# Generated by FakeRAM 2.0
VERSION 5.7 ;
BUSBITCHARS "[]" ;
PROPERTYDEFINITIONS
  MACRO width INTEGER ;
  MACRO depth INTEGER ;
  MACRO banks INTEGER ;
END PROPERTYDEFINITIONS
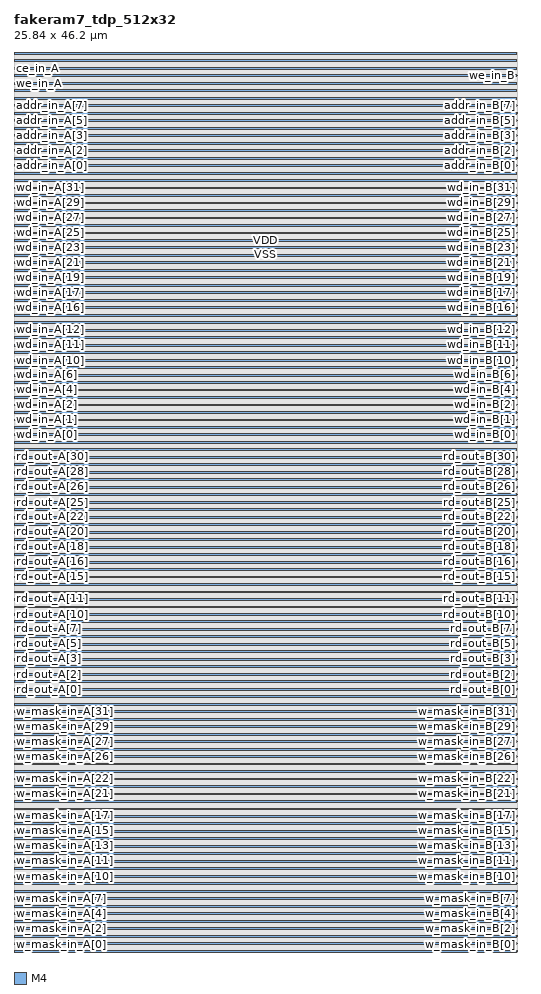
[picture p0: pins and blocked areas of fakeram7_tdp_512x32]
MACRO fakeram7_tdp_512x32
  PROPERTY width 32 ;
  PROPERTY depth 512 ;
  PROPERTY banks 4 ;
  FOREIGN fakeram7_tdp_512x32 0 0 ;
  SYMMETRY X Y ;
  SIZE 25.840 BY 46.200 ;
  CLASS BLOCK ;
  PIN w_mask_in_A[0]
    DIRECTION INPUT ;
    USE SIGNAL ;
    SHAPE ABUTMENT ;
    PORT
      LAYER M4 ;
      RECT 0.000 0.048 0.024 0.072 ;
    END
  END w_mask_in_A[0]
  PIN w_mask_in_B[0]
    DIRECTION INPUT ;
    USE SIGNAL ;
    SHAPE ABUTMENT ;
    PORT
      LAYER M4 ;
      RECT 25.816 0.048 25.840 0.072 ;
    END
  END w_mask_in_B[0]
  PIN w_mask_in_A[1]
    DIRECTION INPUT ;
    USE SIGNAL ;
    SHAPE ABUTMENT ;
    PORT
      LAYER M4 ;
      RECT 0.000 0.432 0.024 0.456 ;
    END
  END w_mask_in_A[1]
  PIN w_mask_in_B[1]
    DIRECTION INPUT ;
    USE SIGNAL ;
    SHAPE ABUTMENT ;
    PORT
      LAYER M4 ;
      RECT 25.816 0.432 25.840 0.456 ;
    END
  END w_mask_in_B[1]
  PIN w_mask_in_A[2]
    DIRECTION INPUT ;
    USE SIGNAL ;
    SHAPE ABUTMENT ;
    PORT
      LAYER M4 ;
      RECT 0.000 0.816 0.024 0.840 ;
    END
  END w_mask_in_A[2]
  PIN w_mask_in_B[2]
    DIRECTION INPUT ;
    USE SIGNAL ;
    SHAPE ABUTMENT ;
    PORT
      LAYER M4 ;
      RECT 25.816 0.816 25.840 0.840 ;
    END
  END w_mask_in_B[2]
  PIN w_mask_in_A[3]
    DIRECTION INPUT ;
    USE SIGNAL ;
    SHAPE ABUTMENT ;
    PORT
      LAYER M4 ;
      RECT 0.000 1.200 0.024 1.224 ;
    END
  END w_mask_in_A[3]
  PIN w_mask_in_B[3]
    DIRECTION INPUT ;
    USE SIGNAL ;
    SHAPE ABUTMENT ;
    PORT
      LAYER M4 ;
      RECT 25.816 1.200 25.840 1.224 ;
    END
  END w_mask_in_B[3]
  PIN w_mask_in_A[4]
    DIRECTION INPUT ;
    USE SIGNAL ;
    SHAPE ABUTMENT ;
    PORT
      LAYER M4 ;
      RECT 0.000 1.584 0.024 1.608 ;
    END
  END w_mask_in_A[4]
  PIN w_mask_in_B[4]
    DIRECTION INPUT ;
    USE SIGNAL ;
    SHAPE ABUTMENT ;
    PORT
      LAYER M4 ;
      RECT 25.816 1.584 25.840 1.608 ;
    END
  END w_mask_in_B[4]
  PIN w_mask_in_A[5]
    DIRECTION INPUT ;
    USE SIGNAL ;
    SHAPE ABUTMENT ;
    PORT
      LAYER M4 ;
      RECT 0.000 1.968 0.024 1.992 ;
    END
  END w_mask_in_A[5]
  PIN w_mask_in_B[5]
    DIRECTION INPUT ;
    USE SIGNAL ;
    SHAPE ABUTMENT ;
    PORT
      LAYER M4 ;
      RECT 25.816 1.968 25.840 1.992 ;
    END
  END w_mask_in_B[5]
  PIN w_mask_in_A[6]
    DIRECTION INPUT ;
    USE SIGNAL ;
    SHAPE ABUTMENT ;
    PORT
      LAYER M4 ;
      RECT 0.000 2.352 0.024 2.376 ;
    END
  END w_mask_in_A[6]
  PIN w_mask_in_B[6]
    DIRECTION INPUT ;
    USE SIGNAL ;
    SHAPE ABUTMENT ;
    PORT
      LAYER M4 ;
      RECT 25.816 2.352 25.840 2.376 ;
    END
  END w_mask_in_B[6]
  PIN w_mask_in_A[7]
    DIRECTION INPUT ;
    USE SIGNAL ;
    SHAPE ABUTMENT ;
    PORT
      LAYER M4 ;
      RECT 0.000 2.736 0.024 2.760 ;
    END
  END w_mask_in_A[7]
  PIN w_mask_in_B[7]
    DIRECTION INPUT ;
    USE SIGNAL ;
    SHAPE ABUTMENT ;
    PORT
      LAYER M4 ;
      RECT 25.816 2.736 25.840 2.760 ;
    END
  END w_mask_in_B[7]
  PIN w_mask_in_A[8]
    DIRECTION INPUT ;
    USE SIGNAL ;
    SHAPE ABUTMENT ;
    PORT
      LAYER M4 ;
      RECT 0.000 3.120 0.024 3.144 ;
    END
  END w_mask_in_A[8]
  PIN w_mask_in_B[8]
    DIRECTION INPUT ;
    USE SIGNAL ;
    SHAPE ABUTMENT ;
    PORT
      LAYER M4 ;
      RECT 25.816 3.120 25.840 3.144 ;
    END
  END w_mask_in_B[8]
  PIN w_mask_in_A[9]
    DIRECTION INPUT ;
    USE SIGNAL ;
    SHAPE ABUTMENT ;
    PORT
      LAYER M4 ;
      RECT 0.000 3.504 0.024 3.528 ;
    END
  END w_mask_in_A[9]
  PIN w_mask_in_B[9]
    DIRECTION INPUT ;
    USE SIGNAL ;
    SHAPE ABUTMENT ;
    PORT
      LAYER M4 ;
      RECT 25.816 3.504 25.840 3.528 ;
    END
  END w_mask_in_B[9]
  PIN w_mask_in_A[10]
    DIRECTION INPUT ;
    USE SIGNAL ;
    SHAPE ABUTMENT ;
    PORT
      LAYER M4 ;
      RECT 0.000 3.888 0.024 3.912 ;
    END
  END w_mask_in_A[10]
  PIN w_mask_in_B[10]
    DIRECTION INPUT ;
    USE SIGNAL ;
    SHAPE ABUTMENT ;
    PORT
      LAYER M4 ;
      RECT 25.816 3.888 25.840 3.912 ;
    END
  END w_mask_in_B[10]
  PIN w_mask_in_A[11]
    DIRECTION INPUT ;
    USE SIGNAL ;
    SHAPE ABUTMENT ;
    PORT
      LAYER M4 ;
      RECT 0.000 4.272 0.024 4.296 ;
    END
  END w_mask_in_A[11]
  PIN w_mask_in_B[11]
    DIRECTION INPUT ;
    USE SIGNAL ;
    SHAPE ABUTMENT ;
    PORT
      LAYER M4 ;
      RECT 25.816 4.272 25.840 4.296 ;
    END
  END w_mask_in_B[11]
  PIN w_mask_in_A[12]
    DIRECTION INPUT ;
    USE SIGNAL ;
    SHAPE ABUTMENT ;
    PORT
      LAYER M4 ;
      RECT 0.000 4.656 0.024 4.680 ;
    END
  END w_mask_in_A[12]
  PIN w_mask_in_B[12]
    DIRECTION INPUT ;
    USE SIGNAL ;
    SHAPE ABUTMENT ;
    PORT
      LAYER M4 ;
      RECT 25.816 4.656 25.840 4.680 ;
    END
  END w_mask_in_B[12]
  PIN w_mask_in_A[13]
    DIRECTION INPUT ;
    USE SIGNAL ;
    SHAPE ABUTMENT ;
    PORT
      LAYER M4 ;
      RECT 0.000 5.040 0.024 5.064 ;
    END
  END w_mask_in_A[13]
  PIN w_mask_in_B[13]
    DIRECTION INPUT ;
    USE SIGNAL ;
    SHAPE ABUTMENT ;
    PORT
      LAYER M4 ;
      RECT 25.816 5.040 25.840 5.064 ;
    END
  END w_mask_in_B[13]
  PIN w_mask_in_A[14]
    DIRECTION INPUT ;
    USE SIGNAL ;
    SHAPE ABUTMENT ;
    PORT
      LAYER M4 ;
      RECT 0.000 5.424 0.024 5.448 ;
    END
  END w_mask_in_A[14]
  PIN w_mask_in_B[14]
    DIRECTION INPUT ;
    USE SIGNAL ;
    SHAPE ABUTMENT ;
    PORT
      LAYER M4 ;
      RECT 25.816 5.424 25.840 5.448 ;
    END
  END w_mask_in_B[14]
  PIN w_mask_in_A[15]
    DIRECTION INPUT ;
    USE SIGNAL ;
    SHAPE ABUTMENT ;
    PORT
      LAYER M4 ;
      RECT 0.000 5.808 0.024 5.832 ;
    END
  END w_mask_in_A[15]
  PIN w_mask_in_B[15]
    DIRECTION INPUT ;
    USE SIGNAL ;
    SHAPE ABUTMENT ;
    PORT
      LAYER M4 ;
      RECT 25.816 5.808 25.840 5.832 ;
    END
  END w_mask_in_B[15]
  PIN w_mask_in_A[16]
    DIRECTION INPUT ;
    USE SIGNAL ;
    SHAPE ABUTMENT ;
    PORT
      LAYER M4 ;
      RECT 0.000 6.192 0.024 6.216 ;
    END
  END w_mask_in_A[16]
  PIN w_mask_in_B[16]
    DIRECTION INPUT ;
    USE SIGNAL ;
    SHAPE ABUTMENT ;
    PORT
      LAYER M4 ;
      RECT 25.816 6.192 25.840 6.216 ;
    END
  END w_mask_in_B[16]
  PIN w_mask_in_A[17]
    DIRECTION INPUT ;
    USE SIGNAL ;
    SHAPE ABUTMENT ;
    PORT
      LAYER M4 ;
      RECT 0.000 6.576 0.024 6.600 ;
    END
  END w_mask_in_A[17]
  PIN w_mask_in_B[17]
    DIRECTION INPUT ;
    USE SIGNAL ;
    SHAPE ABUTMENT ;
    PORT
      LAYER M4 ;
      RECT 25.816 6.576 25.840 6.600 ;
    END
  END w_mask_in_B[17]
  PIN w_mask_in_A[18]
    DIRECTION INPUT ;
    USE SIGNAL ;
    SHAPE ABUTMENT ;
    PORT
      LAYER M4 ;
      RECT 0.000 6.960 0.024 6.984 ;
    END
  END w_mask_in_A[18]
  PIN w_mask_in_B[18]
    DIRECTION INPUT ;
    USE SIGNAL ;
    SHAPE ABUTMENT ;
    PORT
      LAYER M4 ;
      RECT 25.816 6.960 25.840 6.984 ;
    END
  END w_mask_in_B[18]
  PIN w_mask_in_A[19]
    DIRECTION INPUT ;
    USE SIGNAL ;
    SHAPE ABUTMENT ;
    PORT
      LAYER M4 ;
      RECT 0.000 7.344 0.024 7.368 ;
    END
  END w_mask_in_A[19]
  PIN w_mask_in_B[19]
    DIRECTION INPUT ;
    USE SIGNAL ;
    SHAPE ABUTMENT ;
    PORT
      LAYER M4 ;
      RECT 25.816 7.344 25.840 7.368 ;
    END
  END w_mask_in_B[19]
  PIN w_mask_in_A[20]
    DIRECTION INPUT ;
    USE SIGNAL ;
    SHAPE ABUTMENT ;
    PORT
      LAYER M4 ;
      RECT 0.000 7.728 0.024 7.752 ;
    END
  END w_mask_in_A[20]
  PIN w_mask_in_B[20]
    DIRECTION INPUT ;
    USE SIGNAL ;
    SHAPE ABUTMENT ;
    PORT
      LAYER M4 ;
      RECT 25.816 7.728 25.840 7.752 ;
    END
  END w_mask_in_B[20]
  PIN w_mask_in_A[21]
    DIRECTION INPUT ;
    USE SIGNAL ;
    SHAPE ABUTMENT ;
    PORT
      LAYER M4 ;
      RECT 0.000 8.112 0.024 8.136 ;
    END
  END w_mask_in_A[21]
  PIN w_mask_in_B[21]
    DIRECTION INPUT ;
    USE SIGNAL ;
    SHAPE ABUTMENT ;
    PORT
      LAYER M4 ;
      RECT 25.816 8.112 25.840 8.136 ;
    END
  END w_mask_in_B[21]
  PIN w_mask_in_A[22]
    DIRECTION INPUT ;
    USE SIGNAL ;
    SHAPE ABUTMENT ;
    PORT
      LAYER M4 ;
      RECT 0.000 8.496 0.024 8.520 ;
    END
  END w_mask_in_A[22]
  PIN w_mask_in_B[22]
    DIRECTION INPUT ;
    USE SIGNAL ;
    SHAPE ABUTMENT ;
    PORT
      LAYER M4 ;
      RECT 25.816 8.496 25.840 8.520 ;
    END
  END w_mask_in_B[22]
  PIN w_mask_in_A[23]
    DIRECTION INPUT ;
    USE SIGNAL ;
    SHAPE ABUTMENT ;
    PORT
      LAYER M4 ;
      RECT 0.000 8.880 0.024 8.904 ;
    END
  END w_mask_in_A[23]
  PIN w_mask_in_B[23]
    DIRECTION INPUT ;
    USE SIGNAL ;
    SHAPE ABUTMENT ;
    PORT
      LAYER M4 ;
      RECT 25.816 8.880 25.840 8.904 ;
    END
  END w_mask_in_B[23]
  PIN w_mask_in_A[24]
    DIRECTION INPUT ;
    USE SIGNAL ;
    SHAPE ABUTMENT ;
    PORT
      LAYER M4 ;
      RECT 0.000 9.264 0.024 9.288 ;
    END
  END w_mask_in_A[24]
  PIN w_mask_in_B[24]
    DIRECTION INPUT ;
    USE SIGNAL ;
    SHAPE ABUTMENT ;
    PORT
      LAYER M4 ;
      RECT 25.816 9.264 25.840 9.288 ;
    END
  END w_mask_in_B[24]
  PIN w_mask_in_A[25]
    DIRECTION INPUT ;
    USE SIGNAL ;
    SHAPE ABUTMENT ;
    PORT
      LAYER M4 ;
      RECT 0.000 9.648 0.024 9.672 ;
    END
  END w_mask_in_A[25]
  PIN w_mask_in_B[25]
    DIRECTION INPUT ;
    USE SIGNAL ;
    SHAPE ABUTMENT ;
    PORT
      LAYER M4 ;
      RECT 25.816 9.648 25.840 9.672 ;
    END
  END w_mask_in_B[25]
  PIN w_mask_in_A[26]
    DIRECTION INPUT ;
    USE SIGNAL ;
    SHAPE ABUTMENT ;
    PORT
      LAYER M4 ;
      RECT 0.000 10.032 0.024 10.056 ;
    END
  END w_mask_in_A[26]
  PIN w_mask_in_B[26]
    DIRECTION INPUT ;
    USE SIGNAL ;
    SHAPE ABUTMENT ;
    PORT
      LAYER M4 ;
      RECT 25.816 10.032 25.840 10.056 ;
    END
  END w_mask_in_B[26]
  PIN w_mask_in_A[27]
    DIRECTION INPUT ;
    USE SIGNAL ;
    SHAPE ABUTMENT ;
    PORT
      LAYER M4 ;
      RECT 0.000 10.416 0.024 10.440 ;
    END
  END w_mask_in_A[27]
  PIN w_mask_in_B[27]
    DIRECTION INPUT ;
    USE SIGNAL ;
    SHAPE ABUTMENT ;
    PORT
      LAYER M4 ;
      RECT 25.816 10.416 25.840 10.440 ;
    END
  END w_mask_in_B[27]
  PIN w_mask_in_A[28]
    DIRECTION INPUT ;
    USE SIGNAL ;
    SHAPE ABUTMENT ;
    PORT
      LAYER M4 ;
      RECT 0.000 10.800 0.024 10.824 ;
    END
  END w_mask_in_A[28]
  PIN w_mask_in_B[28]
    DIRECTION INPUT ;
    USE SIGNAL ;
    SHAPE ABUTMENT ;
    PORT
      LAYER M4 ;
      RECT 25.816 10.800 25.840 10.824 ;
    END
  END w_mask_in_B[28]
  PIN w_mask_in_A[29]
    DIRECTION INPUT ;
    USE SIGNAL ;
    SHAPE ABUTMENT ;
    PORT
      LAYER M4 ;
      RECT 0.000 11.184 0.024 11.208 ;
    END
  END w_mask_in_A[29]
  PIN w_mask_in_B[29]
    DIRECTION INPUT ;
    USE SIGNAL ;
    SHAPE ABUTMENT ;
    PORT
      LAYER M4 ;
      RECT 25.816 11.184 25.840 11.208 ;
    END
  END w_mask_in_B[29]
  PIN w_mask_in_A[30]
    DIRECTION INPUT ;
    USE SIGNAL ;
    SHAPE ABUTMENT ;
    PORT
      LAYER M4 ;
      RECT 0.000 11.568 0.024 11.592 ;
    END
  END w_mask_in_A[30]
  PIN w_mask_in_B[30]
    DIRECTION INPUT ;
    USE SIGNAL ;
    SHAPE ABUTMENT ;
    PORT
      LAYER M4 ;
      RECT 25.816 11.568 25.840 11.592 ;
    END
  END w_mask_in_B[30]
  PIN w_mask_in_A[31]
    DIRECTION INPUT ;
    USE SIGNAL ;
    SHAPE ABUTMENT ;
    PORT
      LAYER M4 ;
      RECT 0.000 11.952 0.024 11.976 ;
    END
  END w_mask_in_A[31]
  PIN w_mask_in_B[31]
    DIRECTION INPUT ;
    USE SIGNAL ;
    SHAPE ABUTMENT ;
    PORT
      LAYER M4 ;
      RECT 25.816 11.952 25.840 11.976 ;
    END
  END w_mask_in_B[31]
  PIN rd_out_A[0]
    DIRECTION OUTPUT ;
    USE SIGNAL ;
    SHAPE ABUTMENT ;
    PORT
      LAYER M4 ;
      RECT 0.000 13.488 0.024 13.512 ;
    END
  END rd_out_A[0]
  PIN rd_out_B[0]
    DIRECTION OUTPUT ;
    USE SIGNAL ;
    SHAPE ABUTMENT ;
    PORT
      LAYER M4 ;
      RECT 25.816 13.488 25.840 13.512 ;
    END
  END rd_out_B[0]
  PIN rd_out_A[1]
    DIRECTION OUTPUT ;
    USE SIGNAL ;
    SHAPE ABUTMENT ;
    PORT
      LAYER M4 ;
      RECT 0.000 13.872 0.024 13.896 ;
    END
  END rd_out_A[1]
  PIN rd_out_B[1]
    DIRECTION OUTPUT ;
    USE SIGNAL ;
    SHAPE ABUTMENT ;
    PORT
      LAYER M4 ;
      RECT 25.816 13.872 25.840 13.896 ;
    END
  END rd_out_B[1]
  PIN rd_out_A[2]
    DIRECTION OUTPUT ;
    USE SIGNAL ;
    SHAPE ABUTMENT ;
    PORT
      LAYER M4 ;
      RECT 0.000 14.256 0.024 14.280 ;
    END
  END rd_out_A[2]
  PIN rd_out_B[2]
    DIRECTION OUTPUT ;
    USE SIGNAL ;
    SHAPE ABUTMENT ;
    PORT
      LAYER M4 ;
      RECT 25.816 14.256 25.840 14.280 ;
    END
  END rd_out_B[2]
  PIN rd_out_A[3]
    DIRECTION OUTPUT ;
    USE SIGNAL ;
    SHAPE ABUTMENT ;
    PORT
      LAYER M4 ;
      RECT 0.000 14.640 0.024 14.664 ;
    END
  END rd_out_A[3]
  PIN rd_out_B[3]
    DIRECTION OUTPUT ;
    USE SIGNAL ;
    SHAPE ABUTMENT ;
    PORT
      LAYER M4 ;
      RECT 25.816 14.640 25.840 14.664 ;
    END
  END rd_out_B[3]
  PIN rd_out_A[4]
    DIRECTION OUTPUT ;
    USE SIGNAL ;
    SHAPE ABUTMENT ;
    PORT
      LAYER M4 ;
      RECT 0.000 15.024 0.024 15.048 ;
    END
  END rd_out_A[4]
  PIN rd_out_B[4]
    DIRECTION OUTPUT ;
    USE SIGNAL ;
    SHAPE ABUTMENT ;
    PORT
      LAYER M4 ;
      RECT 25.816 15.024 25.840 15.048 ;
    END
  END rd_out_B[4]
  PIN rd_out_A[5]
    DIRECTION OUTPUT ;
    USE SIGNAL ;
    SHAPE ABUTMENT ;
    PORT
      LAYER M4 ;
      RECT 0.000 15.408 0.024 15.432 ;
    END
  END rd_out_A[5]
  PIN rd_out_B[5]
    DIRECTION OUTPUT ;
    USE SIGNAL ;
    SHAPE ABUTMENT ;
    PORT
      LAYER M4 ;
      RECT 25.816 15.408 25.840 15.432 ;
    END
  END rd_out_B[5]
  PIN rd_out_A[6]
    DIRECTION OUTPUT ;
    USE SIGNAL ;
    SHAPE ABUTMENT ;
    PORT
      LAYER M4 ;
      RECT 0.000 15.792 0.024 15.816 ;
    END
  END rd_out_A[6]
  PIN rd_out_B[6]
    DIRECTION OUTPUT ;
    USE SIGNAL ;
    SHAPE ABUTMENT ;
    PORT
      LAYER M4 ;
      RECT 25.816 15.792 25.840 15.816 ;
    END
  END rd_out_B[6]
  PIN rd_out_A[7]
    DIRECTION OUTPUT ;
    USE SIGNAL ;
    SHAPE ABUTMENT ;
    PORT
      LAYER M4 ;
      RECT 0.000 16.176 0.024 16.200 ;
    END
  END rd_out_A[7]
  PIN rd_out_B[7]
    DIRECTION OUTPUT ;
    USE SIGNAL ;
    SHAPE ABUTMENT ;
    PORT
      LAYER M4 ;
      RECT 25.816 16.176 25.840 16.200 ;
    END
  END rd_out_B[7]
  PIN rd_out_A[8]
    DIRECTION OUTPUT ;
    USE SIGNAL ;
    SHAPE ABUTMENT ;
    PORT
      LAYER M4 ;
      RECT 0.000 16.560 0.024 16.584 ;
    END
  END rd_out_A[8]
  PIN rd_out_B[8]
    DIRECTION OUTPUT ;
    USE SIGNAL ;
    SHAPE ABUTMENT ;
    PORT
      LAYER M4 ;
      RECT 25.816 16.560 25.840 16.584 ;
    END
  END rd_out_B[8]
  PIN rd_out_A[9]
    DIRECTION OUTPUT ;
    USE SIGNAL ;
    SHAPE ABUTMENT ;
    PORT
      LAYER M4 ;
      RECT 0.000 16.944 0.024 16.968 ;
    END
  END rd_out_A[9]
  PIN rd_out_B[9]
    DIRECTION OUTPUT ;
    USE SIGNAL ;
    SHAPE ABUTMENT ;
    PORT
      LAYER M4 ;
      RECT 25.816 16.944 25.840 16.968 ;
    END
  END rd_out_B[9]
  PIN rd_out_A[10]
    DIRECTION OUTPUT ;
    USE SIGNAL ;
    SHAPE ABUTMENT ;
    PORT
      LAYER M4 ;
      RECT 0.000 17.328 0.024 17.352 ;
    END
  END rd_out_A[10]
  PIN rd_out_B[10]
    DIRECTION OUTPUT ;
    USE SIGNAL ;
    SHAPE ABUTMENT ;
    PORT
      LAYER M4 ;
      RECT 25.816 17.328 25.840 17.352 ;
    END
  END rd_out_B[10]
  PIN rd_out_A[11]
    DIRECTION OUTPUT ;
    USE SIGNAL ;
    SHAPE ABUTMENT ;
    PORT
      LAYER M4 ;
      RECT 0.000 17.712 0.024 17.736 ;
    END
  END rd_out_A[11]
  PIN rd_out_B[11]
    DIRECTION OUTPUT ;
    USE SIGNAL ;
    SHAPE ABUTMENT ;
    PORT
      LAYER M4 ;
      RECT 25.816 17.712 25.840 17.736 ;
    END
  END rd_out_B[11]
  PIN rd_out_A[12]
    DIRECTION OUTPUT ;
    USE SIGNAL ;
    SHAPE ABUTMENT ;
    PORT
      LAYER M4 ;
      RECT 0.000 18.096 0.024 18.120 ;
    END
  END rd_out_A[12]
  PIN rd_out_B[12]
    DIRECTION OUTPUT ;
    USE SIGNAL ;
    SHAPE ABUTMENT ;
    PORT
      LAYER M4 ;
      RECT 25.816 18.096 25.840 18.120 ;
    END
  END rd_out_B[12]
  PIN rd_out_A[13]
    DIRECTION OUTPUT ;
    USE SIGNAL ;
    SHAPE ABUTMENT ;
    PORT
      LAYER M4 ;
      RECT 0.000 18.480 0.024 18.504 ;
    END
  END rd_out_A[13]
  PIN rd_out_B[13]
    DIRECTION OUTPUT ;
    USE SIGNAL ;
    SHAPE ABUTMENT ;
    PORT
      LAYER M4 ;
      RECT 25.816 18.480 25.840 18.504 ;
    END
  END rd_out_B[13]
  PIN rd_out_A[14]
    DIRECTION OUTPUT ;
    USE SIGNAL ;
    SHAPE ABUTMENT ;
    PORT
      LAYER M4 ;
      RECT 0.000 18.864 0.024 18.888 ;
    END
  END rd_out_A[14]
  PIN rd_out_B[14]
    DIRECTION OUTPUT ;
    USE SIGNAL ;
    SHAPE ABUTMENT ;
    PORT
      LAYER M4 ;
      RECT 25.816 18.864 25.840 18.888 ;
    END
  END rd_out_B[14]
  PIN rd_out_A[15]
    DIRECTION OUTPUT ;
    USE SIGNAL ;
    SHAPE ABUTMENT ;
    PORT
      LAYER M4 ;
      RECT 0.000 19.248 0.024 19.272 ;
    END
  END rd_out_A[15]
  PIN rd_out_B[15]
    DIRECTION OUTPUT ;
    USE SIGNAL ;
    SHAPE ABUTMENT ;
    PORT
      LAYER M4 ;
      RECT 25.816 19.248 25.840 19.272 ;
    END
  END rd_out_B[15]
  PIN rd_out_A[16]
    DIRECTION OUTPUT ;
    USE SIGNAL ;
    SHAPE ABUTMENT ;
    PORT
      LAYER M4 ;
      RECT 0.000 19.632 0.024 19.656 ;
    END
  END rd_out_A[16]
  PIN rd_out_B[16]
    DIRECTION OUTPUT ;
    USE SIGNAL ;
    SHAPE ABUTMENT ;
    PORT
      LAYER M4 ;
      RECT 25.816 19.632 25.840 19.656 ;
    END
  END rd_out_B[16]
  PIN rd_out_A[17]
    DIRECTION OUTPUT ;
    USE SIGNAL ;
    SHAPE ABUTMENT ;
    PORT
      LAYER M4 ;
      RECT 0.000 20.016 0.024 20.040 ;
    END
  END rd_out_A[17]
  PIN rd_out_B[17]
    DIRECTION OUTPUT ;
    USE SIGNAL ;
    SHAPE ABUTMENT ;
    PORT
      LAYER M4 ;
      RECT 25.816 20.016 25.840 20.040 ;
    END
  END rd_out_B[17]
  PIN rd_out_A[18]
    DIRECTION OUTPUT ;
    USE SIGNAL ;
    SHAPE ABUTMENT ;
    PORT
      LAYER M4 ;
      RECT 0.000 20.400 0.024 20.424 ;
    END
  END rd_out_A[18]
  PIN rd_out_B[18]
    DIRECTION OUTPUT ;
    USE SIGNAL ;
    SHAPE ABUTMENT ;
    PORT
      LAYER M4 ;
      RECT 25.816 20.400 25.840 20.424 ;
    END
  END rd_out_B[18]
  PIN rd_out_A[19]
    DIRECTION OUTPUT ;
    USE SIGNAL ;
    SHAPE ABUTMENT ;
    PORT
      LAYER M4 ;
      RECT 0.000 20.784 0.024 20.808 ;
    END
  END rd_out_A[19]
  PIN rd_out_B[19]
    DIRECTION OUTPUT ;
    USE SIGNAL ;
    SHAPE ABUTMENT ;
    PORT
      LAYER M4 ;
      RECT 25.816 20.784 25.840 20.808 ;
    END
  END rd_out_B[19]
  PIN rd_out_A[20]
    DIRECTION OUTPUT ;
    USE SIGNAL ;
    SHAPE ABUTMENT ;
    PORT
      LAYER M4 ;
      RECT 0.000 21.168 0.024 21.192 ;
    END
  END rd_out_A[20]
  PIN rd_out_B[20]
    DIRECTION OUTPUT ;
    USE SIGNAL ;
    SHAPE ABUTMENT ;
    PORT
      LAYER M4 ;
      RECT 25.816 21.168 25.840 21.192 ;
    END
  END rd_out_B[20]
  PIN rd_out_A[21]
    DIRECTION OUTPUT ;
    USE SIGNAL ;
    SHAPE ABUTMENT ;
    PORT
      LAYER M4 ;
      RECT 0.000 21.552 0.024 21.576 ;
    END
  END rd_out_A[21]
  PIN rd_out_B[21]
    DIRECTION OUTPUT ;
    USE SIGNAL ;
    SHAPE ABUTMENT ;
    PORT
      LAYER M4 ;
      RECT 25.816 21.552 25.840 21.576 ;
    END
  END rd_out_B[21]
  PIN rd_out_A[22]
    DIRECTION OUTPUT ;
    USE SIGNAL ;
    SHAPE ABUTMENT ;
    PORT
      LAYER M4 ;
      RECT 0.000 21.936 0.024 21.960 ;
    END
  END rd_out_A[22]
  PIN rd_out_B[22]
    DIRECTION OUTPUT ;
    USE SIGNAL ;
    SHAPE ABUTMENT ;
    PORT
      LAYER M4 ;
      RECT 25.816 21.936 25.840 21.960 ;
    END
  END rd_out_B[22]
  PIN rd_out_A[23]
    DIRECTION OUTPUT ;
    USE SIGNAL ;
    SHAPE ABUTMENT ;
    PORT
      LAYER M4 ;
      RECT 0.000 22.320 0.024 22.344 ;
    END
  END rd_out_A[23]
  PIN rd_out_B[23]
    DIRECTION OUTPUT ;
    USE SIGNAL ;
    SHAPE ABUTMENT ;
    PORT
      LAYER M4 ;
      RECT 25.816 22.320 25.840 22.344 ;
    END
  END rd_out_B[23]
  PIN rd_out_A[24]
    DIRECTION OUTPUT ;
    USE SIGNAL ;
    SHAPE ABUTMENT ;
    PORT
      LAYER M4 ;
      RECT 0.000 22.704 0.024 22.728 ;
    END
  END rd_out_A[24]
  PIN rd_out_B[24]
    DIRECTION OUTPUT ;
    USE SIGNAL ;
    SHAPE ABUTMENT ;
    PORT
      LAYER M4 ;
      RECT 25.816 22.704 25.840 22.728 ;
    END
  END rd_out_B[24]
  PIN rd_out_A[25]
    DIRECTION OUTPUT ;
    USE SIGNAL ;
    SHAPE ABUTMENT ;
    PORT
      LAYER M4 ;
      RECT 0.000 23.088 0.024 23.112 ;
    END
  END rd_out_A[25]
  PIN rd_out_B[25]
    DIRECTION OUTPUT ;
    USE SIGNAL ;
    SHAPE ABUTMENT ;
    PORT
      LAYER M4 ;
      RECT 25.816 23.088 25.840 23.112 ;
    END
  END rd_out_B[25]
  PIN rd_out_A[26]
    DIRECTION OUTPUT ;
    USE SIGNAL ;
    SHAPE ABUTMENT ;
    PORT
      LAYER M4 ;
      RECT 0.000 23.472 0.024 23.496 ;
    END
  END rd_out_A[26]
  PIN rd_out_B[26]
    DIRECTION OUTPUT ;
    USE SIGNAL ;
    SHAPE ABUTMENT ;
    PORT
      LAYER M4 ;
      RECT 25.816 23.472 25.840 23.496 ;
    END
  END rd_out_B[26]
  PIN rd_out_A[27]
    DIRECTION OUTPUT ;
    USE SIGNAL ;
    SHAPE ABUTMENT ;
    PORT
      LAYER M4 ;
      RECT 0.000 23.856 0.024 23.880 ;
    END
  END rd_out_A[27]
  PIN rd_out_B[27]
    DIRECTION OUTPUT ;
    USE SIGNAL ;
    SHAPE ABUTMENT ;
    PORT
      LAYER M4 ;
      RECT 25.816 23.856 25.840 23.880 ;
    END
  END rd_out_B[27]
  PIN rd_out_A[28]
    DIRECTION OUTPUT ;
    USE SIGNAL ;
    SHAPE ABUTMENT ;
    PORT
      LAYER M4 ;
      RECT 0.000 24.240 0.024 24.264 ;
    END
  END rd_out_A[28]
  PIN rd_out_B[28]
    DIRECTION OUTPUT ;
    USE SIGNAL ;
    SHAPE ABUTMENT ;
    PORT
      LAYER M4 ;
      RECT 25.816 24.240 25.840 24.264 ;
    END
  END rd_out_B[28]
  PIN rd_out_A[29]
    DIRECTION OUTPUT ;
    USE SIGNAL ;
    SHAPE ABUTMENT ;
    PORT
      LAYER M4 ;
      RECT 0.000 24.624 0.024 24.648 ;
    END
  END rd_out_A[29]
  PIN rd_out_B[29]
    DIRECTION OUTPUT ;
    USE SIGNAL ;
    SHAPE ABUTMENT ;
    PORT
      LAYER M4 ;
      RECT 25.816 24.624 25.840 24.648 ;
    END
  END rd_out_B[29]
  PIN rd_out_A[30]
    DIRECTION OUTPUT ;
    USE SIGNAL ;
    SHAPE ABUTMENT ;
    PORT
      LAYER M4 ;
      RECT 0.000 25.008 0.024 25.032 ;
    END
  END rd_out_A[30]
  PIN rd_out_B[30]
    DIRECTION OUTPUT ;
    USE SIGNAL ;
    SHAPE ABUTMENT ;
    PORT
      LAYER M4 ;
      RECT 25.816 25.008 25.840 25.032 ;
    END
  END rd_out_B[30]
  PIN rd_out_A[31]
    DIRECTION OUTPUT ;
    USE SIGNAL ;
    SHAPE ABUTMENT ;
    PORT
      LAYER M4 ;
      RECT 0.000 25.392 0.024 25.416 ;
    END
  END rd_out_A[31]
  PIN rd_out_B[31]
    DIRECTION OUTPUT ;
    USE SIGNAL ;
    SHAPE ABUTMENT ;
    PORT
      LAYER M4 ;
      RECT 25.816 25.392 25.840 25.416 ;
    END
  END rd_out_B[31]
  PIN wd_in_A[0]
    DIRECTION INPUT ;
    USE SIGNAL ;
    SHAPE ABUTMENT ;
    PORT
      LAYER M4 ;
      RECT 0.000 26.928 0.024 26.952 ;
    END
  END wd_in_A[0]
  PIN wd_in_B[0]
    DIRECTION INPUT ;
    USE SIGNAL ;
    SHAPE ABUTMENT ;
    PORT
      LAYER M4 ;
      RECT 25.816 26.928 25.840 26.952 ;
    END
  END wd_in_B[0]
  PIN wd_in_A[1]
    DIRECTION INPUT ;
    USE SIGNAL ;
    SHAPE ABUTMENT ;
    PORT
      LAYER M4 ;
      RECT 0.000 27.312 0.024 27.336 ;
    END
  END wd_in_A[1]
  PIN wd_in_B[1]
    DIRECTION INPUT ;
    USE SIGNAL ;
    SHAPE ABUTMENT ;
    PORT
      LAYER M4 ;
      RECT 25.816 27.312 25.840 27.336 ;
    END
  END wd_in_B[1]
  PIN wd_in_A[2]
    DIRECTION INPUT ;
    USE SIGNAL ;
    SHAPE ABUTMENT ;
    PORT
      LAYER M4 ;
      RECT 0.000 27.696 0.024 27.720 ;
    END
  END wd_in_A[2]
  PIN wd_in_B[2]
    DIRECTION INPUT ;
    USE SIGNAL ;
    SHAPE ABUTMENT ;
    PORT
      LAYER M4 ;
      RECT 25.816 27.696 25.840 27.720 ;
    END
  END wd_in_B[2]
  PIN wd_in_A[3]
    DIRECTION INPUT ;
    USE SIGNAL ;
    SHAPE ABUTMENT ;
    PORT
      LAYER M4 ;
      RECT 0.000 28.080 0.024 28.104 ;
    END
  END wd_in_A[3]
  PIN wd_in_B[3]
    DIRECTION INPUT ;
    USE SIGNAL ;
    SHAPE ABUTMENT ;
    PORT
      LAYER M4 ;
      RECT 25.816 28.080 25.840 28.104 ;
    END
  END wd_in_B[3]
  PIN wd_in_A[4]
    DIRECTION INPUT ;
    USE SIGNAL ;
    SHAPE ABUTMENT ;
    PORT
      LAYER M4 ;
      RECT 0.000 28.464 0.024 28.488 ;
    END
  END wd_in_A[4]
  PIN wd_in_B[4]
    DIRECTION INPUT ;
    USE SIGNAL ;
    SHAPE ABUTMENT ;
    PORT
      LAYER M4 ;
      RECT 25.816 28.464 25.840 28.488 ;
    END
  END wd_in_B[4]
  PIN wd_in_A[5]
    DIRECTION INPUT ;
    USE SIGNAL ;
    SHAPE ABUTMENT ;
    PORT
      LAYER M4 ;
      RECT 0.000 28.848 0.024 28.872 ;
    END
  END wd_in_A[5]
  PIN wd_in_B[5]
    DIRECTION INPUT ;
    USE SIGNAL ;
    SHAPE ABUTMENT ;
    PORT
      LAYER M4 ;
      RECT 25.816 28.848 25.840 28.872 ;
    END
  END wd_in_B[5]
  PIN wd_in_A[6]
    DIRECTION INPUT ;
    USE SIGNAL ;
    SHAPE ABUTMENT ;
    PORT
      LAYER M4 ;
      RECT 0.000 29.232 0.024 29.256 ;
    END
  END wd_in_A[6]
  PIN wd_in_B[6]
    DIRECTION INPUT ;
    USE SIGNAL ;
    SHAPE ABUTMENT ;
    PORT
      LAYER M4 ;
      RECT 25.816 29.232 25.840 29.256 ;
    END
  END wd_in_B[6]
  PIN wd_in_A[7]
    DIRECTION INPUT ;
    USE SIGNAL ;
    SHAPE ABUTMENT ;
    PORT
      LAYER M4 ;
      RECT 0.000 29.616 0.024 29.640 ;
    END
  END wd_in_A[7]
  PIN wd_in_B[7]
    DIRECTION INPUT ;
    USE SIGNAL ;
    SHAPE ABUTMENT ;
    PORT
      LAYER M4 ;
      RECT 25.816 29.616 25.840 29.640 ;
    END
  END wd_in_B[7]
  PIN wd_in_A[8]
    DIRECTION INPUT ;
    USE SIGNAL ;
    SHAPE ABUTMENT ;
    PORT
      LAYER M4 ;
      RECT 0.000 30.000 0.024 30.024 ;
    END
  END wd_in_A[8]
  PIN wd_in_B[8]
    DIRECTION INPUT ;
    USE SIGNAL ;
    SHAPE ABUTMENT ;
    PORT
      LAYER M4 ;
      RECT 25.816 30.000 25.840 30.024 ;
    END
  END wd_in_B[8]
  PIN wd_in_A[9]
    DIRECTION INPUT ;
    USE SIGNAL ;
    SHAPE ABUTMENT ;
    PORT
      LAYER M4 ;
      RECT 0.000 30.384 0.024 30.408 ;
    END
  END wd_in_A[9]
  PIN wd_in_B[9]
    DIRECTION INPUT ;
    USE SIGNAL ;
    SHAPE ABUTMENT ;
    PORT
      LAYER M4 ;
      RECT 25.816 30.384 25.840 30.408 ;
    END
  END wd_in_B[9]
  PIN wd_in_A[10]
    DIRECTION INPUT ;
    USE SIGNAL ;
    SHAPE ABUTMENT ;
    PORT
      LAYER M4 ;
      RECT 0.000 30.768 0.024 30.792 ;
    END
  END wd_in_A[10]
  PIN wd_in_B[10]
    DIRECTION INPUT ;
    USE SIGNAL ;
    SHAPE ABUTMENT ;
    PORT
      LAYER M4 ;
      RECT 25.816 30.768 25.840 30.792 ;
    END
  END wd_in_B[10]
  PIN wd_in_A[11]
    DIRECTION INPUT ;
    USE SIGNAL ;
    SHAPE ABUTMENT ;
    PORT
      LAYER M4 ;
      RECT 0.000 31.152 0.024 31.176 ;
    END
  END wd_in_A[11]
  PIN wd_in_B[11]
    DIRECTION INPUT ;
    USE SIGNAL ;
    SHAPE ABUTMENT ;
    PORT
      LAYER M4 ;
      RECT 25.816 31.152 25.840 31.176 ;
    END
  END wd_in_B[11]
  PIN wd_in_A[12]
    DIRECTION INPUT ;
    USE SIGNAL ;
    SHAPE ABUTMENT ;
    PORT
      LAYER M4 ;
      RECT 0.000 31.536 0.024 31.560 ;
    END
  END wd_in_A[12]
  PIN wd_in_B[12]
    DIRECTION INPUT ;
    USE SIGNAL ;
    SHAPE ABUTMENT ;
    PORT
      LAYER M4 ;
      RECT 25.816 31.536 25.840 31.560 ;
    END
  END wd_in_B[12]
  PIN wd_in_A[13]
    DIRECTION INPUT ;
    USE SIGNAL ;
    SHAPE ABUTMENT ;
    PORT
      LAYER M4 ;
      RECT 0.000 31.920 0.024 31.944 ;
    END
  END wd_in_A[13]
  PIN wd_in_B[13]
    DIRECTION INPUT ;
    USE SIGNAL ;
    SHAPE ABUTMENT ;
    PORT
      LAYER M4 ;
      RECT 25.816 31.920 25.840 31.944 ;
    END
  END wd_in_B[13]
  PIN wd_in_A[14]
    DIRECTION INPUT ;
    USE SIGNAL ;
    SHAPE ABUTMENT ;
    PORT
      LAYER M4 ;
      RECT 0.000 32.304 0.024 32.328 ;
    END
  END wd_in_A[14]
  PIN wd_in_B[14]
    DIRECTION INPUT ;
    USE SIGNAL ;
    SHAPE ABUTMENT ;
    PORT
      LAYER M4 ;
      RECT 25.816 32.304 25.840 32.328 ;
    END
  END wd_in_B[14]
  PIN wd_in_A[15]
    DIRECTION INPUT ;
    USE SIGNAL ;
    SHAPE ABUTMENT ;
    PORT
      LAYER M4 ;
      RECT 0.000 32.688 0.024 32.712 ;
    END
  END wd_in_A[15]
  PIN wd_in_B[15]
    DIRECTION INPUT ;
    USE SIGNAL ;
    SHAPE ABUTMENT ;
    PORT
      LAYER M4 ;
      RECT 25.816 32.688 25.840 32.712 ;
    END
  END wd_in_B[15]
  PIN wd_in_A[16]
    DIRECTION INPUT ;
    USE SIGNAL ;
    SHAPE ABUTMENT ;
    PORT
      LAYER M4 ;
      RECT 0.000 33.072 0.024 33.096 ;
    END
  END wd_in_A[16]
  PIN wd_in_B[16]
    DIRECTION INPUT ;
    USE SIGNAL ;
    SHAPE ABUTMENT ;
    PORT
      LAYER M4 ;
      RECT 25.816 33.072 25.840 33.096 ;
    END
  END wd_in_B[16]
  PIN wd_in_A[17]
    DIRECTION INPUT ;
    USE SIGNAL ;
    SHAPE ABUTMENT ;
    PORT
      LAYER M4 ;
      RECT 0.000 33.456 0.024 33.480 ;
    END
  END wd_in_A[17]
  PIN wd_in_B[17]
    DIRECTION INPUT ;
    USE SIGNAL ;
    SHAPE ABUTMENT ;
    PORT
      LAYER M4 ;
      RECT 25.816 33.456 25.840 33.480 ;
    END
  END wd_in_B[17]
  PIN wd_in_A[18]
    DIRECTION INPUT ;
    USE SIGNAL ;
    SHAPE ABUTMENT ;
    PORT
      LAYER M4 ;
      RECT 0.000 33.840 0.024 33.864 ;
    END
  END wd_in_A[18]
  PIN wd_in_B[18]
    DIRECTION INPUT ;
    USE SIGNAL ;
    SHAPE ABUTMENT ;
    PORT
      LAYER M4 ;
      RECT 25.816 33.840 25.840 33.864 ;
    END
  END wd_in_B[18]
  PIN wd_in_A[19]
    DIRECTION INPUT ;
    USE SIGNAL ;
    SHAPE ABUTMENT ;
    PORT
      LAYER M4 ;
      RECT 0.000 34.224 0.024 34.248 ;
    END
  END wd_in_A[19]
  PIN wd_in_B[19]
    DIRECTION INPUT ;
    USE SIGNAL ;
    SHAPE ABUTMENT ;
    PORT
      LAYER M4 ;
      RECT 25.816 34.224 25.840 34.248 ;
    END
  END wd_in_B[19]
  PIN wd_in_A[20]
    DIRECTION INPUT ;
    USE SIGNAL ;
    SHAPE ABUTMENT ;
    PORT
      LAYER M4 ;
      RECT 0.000 34.608 0.024 34.632 ;
    END
  END wd_in_A[20]
  PIN wd_in_B[20]
    DIRECTION INPUT ;
    USE SIGNAL ;
    SHAPE ABUTMENT ;
    PORT
      LAYER M4 ;
      RECT 25.816 34.608 25.840 34.632 ;
    END
  END wd_in_B[20]
  PIN wd_in_A[21]
    DIRECTION INPUT ;
    USE SIGNAL ;
    SHAPE ABUTMENT ;
    PORT
      LAYER M4 ;
      RECT 0.000 34.992 0.024 35.016 ;
    END
  END wd_in_A[21]
  PIN wd_in_B[21]
    DIRECTION INPUT ;
    USE SIGNAL ;
    SHAPE ABUTMENT ;
    PORT
      LAYER M4 ;
      RECT 25.816 34.992 25.840 35.016 ;
    END
  END wd_in_B[21]
  PIN wd_in_A[22]
    DIRECTION INPUT ;
    USE SIGNAL ;
    SHAPE ABUTMENT ;
    PORT
      LAYER M4 ;
      RECT 0.000 35.376 0.024 35.400 ;
    END
  END wd_in_A[22]
  PIN wd_in_B[22]
    DIRECTION INPUT ;
    USE SIGNAL ;
    SHAPE ABUTMENT ;
    PORT
      LAYER M4 ;
      RECT 25.816 35.376 25.840 35.400 ;
    END
  END wd_in_B[22]
  PIN wd_in_A[23]
    DIRECTION INPUT ;
    USE SIGNAL ;
    SHAPE ABUTMENT ;
    PORT
      LAYER M4 ;
      RECT 0.000 35.760 0.024 35.784 ;
    END
  END wd_in_A[23]
  PIN wd_in_B[23]
    DIRECTION INPUT ;
    USE SIGNAL ;
    SHAPE ABUTMENT ;
    PORT
      LAYER M4 ;
      RECT 25.816 35.760 25.840 35.784 ;
    END
  END wd_in_B[23]
  PIN wd_in_A[24]
    DIRECTION INPUT ;
    USE SIGNAL ;
    SHAPE ABUTMENT ;
    PORT
      LAYER M4 ;
      RECT 0.000 36.144 0.024 36.168 ;
    END
  END wd_in_A[24]
  PIN wd_in_B[24]
    DIRECTION INPUT ;
    USE SIGNAL ;
    SHAPE ABUTMENT ;
    PORT
      LAYER M4 ;
      RECT 25.816 36.144 25.840 36.168 ;
    END
  END wd_in_B[24]
  PIN wd_in_A[25]
    DIRECTION INPUT ;
    USE SIGNAL ;
    SHAPE ABUTMENT ;
    PORT
      LAYER M4 ;
      RECT 0.000 36.528 0.024 36.552 ;
    END
  END wd_in_A[25]
  PIN wd_in_B[25]
    DIRECTION INPUT ;
    USE SIGNAL ;
    SHAPE ABUTMENT ;
    PORT
      LAYER M4 ;
      RECT 25.816 36.528 25.840 36.552 ;
    END
  END wd_in_B[25]
  PIN wd_in_A[26]
    DIRECTION INPUT ;
    USE SIGNAL ;
    SHAPE ABUTMENT ;
    PORT
      LAYER M4 ;
      RECT 0.000 36.912 0.024 36.936 ;
    END
  END wd_in_A[26]
  PIN wd_in_B[26]
    DIRECTION INPUT ;
    USE SIGNAL ;
    SHAPE ABUTMENT ;
    PORT
      LAYER M4 ;
      RECT 25.816 36.912 25.840 36.936 ;
    END
  END wd_in_B[26]
  PIN wd_in_A[27]
    DIRECTION INPUT ;
    USE SIGNAL ;
    SHAPE ABUTMENT ;
    PORT
      LAYER M4 ;
      RECT 0.000 37.296 0.024 37.320 ;
    END
  END wd_in_A[27]
  PIN wd_in_B[27]
    DIRECTION INPUT ;
    USE SIGNAL ;
    SHAPE ABUTMENT ;
    PORT
      LAYER M4 ;
      RECT 25.816 37.296 25.840 37.320 ;
    END
  END wd_in_B[27]
  PIN wd_in_A[28]
    DIRECTION INPUT ;
    USE SIGNAL ;
    SHAPE ABUTMENT ;
    PORT
      LAYER M4 ;
      RECT 0.000 37.680 0.024 37.704 ;
    END
  END wd_in_A[28]
  PIN wd_in_B[28]
    DIRECTION INPUT ;
    USE SIGNAL ;
    SHAPE ABUTMENT ;
    PORT
      LAYER M4 ;
      RECT 25.816 37.680 25.840 37.704 ;
    END
  END wd_in_B[28]
  PIN wd_in_A[29]
    DIRECTION INPUT ;
    USE SIGNAL ;
    SHAPE ABUTMENT ;
    PORT
      LAYER M4 ;
      RECT 0.000 38.064 0.024 38.088 ;
    END
  END wd_in_A[29]
  PIN wd_in_B[29]
    DIRECTION INPUT ;
    USE SIGNAL ;
    SHAPE ABUTMENT ;
    PORT
      LAYER M4 ;
      RECT 25.816 38.064 25.840 38.088 ;
    END
  END wd_in_B[29]
  PIN wd_in_A[30]
    DIRECTION INPUT ;
    USE SIGNAL ;
    SHAPE ABUTMENT ;
    PORT
      LAYER M4 ;
      RECT 0.000 38.448 0.024 38.472 ;
    END
  END wd_in_A[30]
  PIN wd_in_B[30]
    DIRECTION INPUT ;
    USE SIGNAL ;
    SHAPE ABUTMENT ;
    PORT
      LAYER M4 ;
      RECT 25.816 38.448 25.840 38.472 ;
    END
  END wd_in_B[30]
  PIN wd_in_A[31]
    DIRECTION INPUT ;
    USE SIGNAL ;
    SHAPE ABUTMENT ;
    PORT
      LAYER M4 ;
      RECT 0.000 38.832 0.024 38.856 ;
    END
  END wd_in_A[31]
  PIN wd_in_B[31]
    DIRECTION INPUT ;
    USE SIGNAL ;
    SHAPE ABUTMENT ;
    PORT
      LAYER M4 ;
      RECT 25.816 38.832 25.840 38.856 ;
    END
  END wd_in_B[31]
  PIN addr_in_A[0]
    DIRECTION INPUT ;
    USE SIGNAL ;
    SHAPE ABUTMENT ;
    PORT
      LAYER M4 ;
      RECT 0.000 40.368 0.024 40.392 ;
    END
  END addr_in_A[0]
  PIN addr_in_B[0]
    DIRECTION INPUT ;
    USE SIGNAL ;
    SHAPE ABUTMENT ;
    PORT
      LAYER M4 ;
      RECT 25.816 40.368 25.840 40.392 ;
    END
  END addr_in_B[0]
  PIN addr_in_A[1]
    DIRECTION INPUT ;
    USE SIGNAL ;
    SHAPE ABUTMENT ;
    PORT
      LAYER M4 ;
      RECT 0.000 40.752 0.024 40.776 ;
    END
  END addr_in_A[1]
  PIN addr_in_B[1]
    DIRECTION INPUT ;
    USE SIGNAL ;
    SHAPE ABUTMENT ;
    PORT
      LAYER M4 ;
      RECT 25.816 40.752 25.840 40.776 ;
    END
  END addr_in_B[1]
  PIN addr_in_A[2]
    DIRECTION INPUT ;
    USE SIGNAL ;
    SHAPE ABUTMENT ;
    PORT
      LAYER M4 ;
      RECT 0.000 41.136 0.024 41.160 ;
    END
  END addr_in_A[2]
  PIN addr_in_B[2]
    DIRECTION INPUT ;
    USE SIGNAL ;
    SHAPE ABUTMENT ;
    PORT
      LAYER M4 ;
      RECT 25.816 41.136 25.840 41.160 ;
    END
  END addr_in_B[2]
  PIN addr_in_A[3]
    DIRECTION INPUT ;
    USE SIGNAL ;
    SHAPE ABUTMENT ;
    PORT
      LAYER M4 ;
      RECT 0.000 41.520 0.024 41.544 ;
    END
  END addr_in_A[3]
  PIN addr_in_B[3]
    DIRECTION INPUT ;
    USE SIGNAL ;
    SHAPE ABUTMENT ;
    PORT
      LAYER M4 ;
      RECT 25.816 41.520 25.840 41.544 ;
    END
  END addr_in_B[3]
  PIN addr_in_A[4]
    DIRECTION INPUT ;
    USE SIGNAL ;
    SHAPE ABUTMENT ;
    PORT
      LAYER M4 ;
      RECT 0.000 41.904 0.024 41.928 ;
    END
  END addr_in_A[4]
  PIN addr_in_B[4]
    DIRECTION INPUT ;
    USE SIGNAL ;
    SHAPE ABUTMENT ;
    PORT
      LAYER M4 ;
      RECT 25.816 41.904 25.840 41.928 ;
    END
  END addr_in_B[4]
  PIN addr_in_A[5]
    DIRECTION INPUT ;
    USE SIGNAL ;
    SHAPE ABUTMENT ;
    PORT
      LAYER M4 ;
      RECT 0.000 42.288 0.024 42.312 ;
    END
  END addr_in_A[5]
  PIN addr_in_B[5]
    DIRECTION INPUT ;
    USE SIGNAL ;
    SHAPE ABUTMENT ;
    PORT
      LAYER M4 ;
      RECT 25.816 42.288 25.840 42.312 ;
    END
  END addr_in_B[5]
  PIN addr_in_A[6]
    DIRECTION INPUT ;
    USE SIGNAL ;
    SHAPE ABUTMENT ;
    PORT
      LAYER M4 ;
      RECT 0.000 42.672 0.024 42.696 ;
    END
  END addr_in_A[6]
  PIN addr_in_B[6]
    DIRECTION INPUT ;
    USE SIGNAL ;
    SHAPE ABUTMENT ;
    PORT
      LAYER M4 ;
      RECT 25.816 42.672 25.840 42.696 ;
    END
  END addr_in_B[6]
  PIN addr_in_A[7]
    DIRECTION INPUT ;
    USE SIGNAL ;
    SHAPE ABUTMENT ;
    PORT
      LAYER M4 ;
      RECT 0.000 43.056 0.024 43.080 ;
    END
  END addr_in_A[7]
  PIN addr_in_B[7]
    DIRECTION INPUT ;
    USE SIGNAL ;
    SHAPE ABUTMENT ;
    PORT
      LAYER M4 ;
      RECT 25.816 43.056 25.840 43.080 ;
    END
  END addr_in_B[7]
  PIN addr_in_A[8]
    DIRECTION INPUT ;
    USE SIGNAL ;
    SHAPE ABUTMENT ;
    PORT
      LAYER M4 ;
      RECT 0.000 43.440 0.024 43.464 ;
    END
  END addr_in_A[8]
  PIN addr_in_B[8]
    DIRECTION INPUT ;
    USE SIGNAL ;
    SHAPE ABUTMENT ;
    PORT
      LAYER M4 ;
      RECT 25.816 43.440 25.840 43.464 ;
    END
  END addr_in_B[8]
  PIN we_in_A
    DIRECTION INPUT ;
    USE SIGNAL ;
    SHAPE ABUTMENT ;
    PORT
      LAYER M4 ;
      RECT 0.000 44.976 0.024 45.000 ;
    END
  END we_in_A
  PIN we_in_B
    DIRECTION INPUT ;
    USE SIGNAL ;
    SHAPE ABUTMENT ;
    PORT
      LAYER M4 ;
      RECT 25.816 44.976 25.840 45.000 ;
    END
  END we_in_B
  PIN ce_in_A
    DIRECTION INPUT ;
    USE SIGNAL ;
    SHAPE ABUTMENT ;
    PORT
      LAYER M4 ;
      RECT 0.000 45.360 0.024 45.384 ;
    END
  END ce_in_A
  PIN clk_A
    DIRECTION INPUT ;
    USE SIGNAL ;
    SHAPE ABUTMENT ;
    PORT
      LAYER M4 ;
      RECT 0.000 45.744 0.024 45.768 ;
    END
  END clk_A
  PIN ce_in_B
    DIRECTION INPUT ;
    USE SIGNAL ;
    SHAPE ABUTMENT ;
    PORT
      LAYER M4 ;
      RECT 0.000 46.128 0.024 46.152 ;
    END
  END ce_in_B
  PIN clk_B
    DIRECTION INPUT ;
    USE SIGNAL ;
    SHAPE ABUTMENT ;
    PORT
      LAYER M4 ;
      RECT 0.000 46.512 0.024 46.536 ;
    END
  END clk_B
  PIN VSS
    DIRECTION INOUT ;
    USE GROUND ;
    PORT
      LAYER M4 ;
      RECT 0.048 0.000 25.792 0.096 ;
      RECT 0.048 0.768 25.792 0.864 ;
      RECT 0.048 1.536 25.792 1.632 ;
      RECT 0.048 2.304 25.792 2.400 ;
      RECT 0.048 3.072 25.792 3.168 ;
      RECT 0.048 3.840 25.792 3.936 ;
      RECT 0.048 4.608 25.792 4.704 ;
      RECT 0.048 5.376 25.792 5.472 ;
      RECT 0.048 6.144 25.792 6.240 ;
      RECT 0.048 6.912 25.792 7.008 ;
      RECT 0.048 7.680 25.792 7.776 ;
      RECT 0.048 8.448 25.792 8.544 ;
      RECT 0.048 9.216 25.792 9.312 ;
      RECT 0.048 9.984 25.792 10.080 ;
      RECT 0.048 10.752 25.792 10.848 ;
      RECT 0.048 11.520 25.792 11.616 ;
      RECT 0.048 12.288 25.792 12.384 ;
      RECT 0.048 13.056 25.792 13.152 ;
      RECT 0.048 13.824 25.792 13.920 ;
      RECT 0.048 14.592 25.792 14.688 ;
      RECT 0.048 15.360 25.792 15.456 ;
      RECT 0.048 16.128 25.792 16.224 ;
      RECT 0.048 16.896 25.792 16.992 ;
      RECT 0.048 17.664 25.792 17.760 ;
      RECT 0.048 18.432 25.792 18.528 ;
      RECT 0.048 19.200 25.792 19.296 ;
      RECT 0.048 19.968 25.792 20.064 ;
      RECT 0.048 20.736 25.792 20.832 ;
      RECT 0.048 21.504 25.792 21.600 ;
      RECT 0.048 22.272 25.792 22.368 ;
      RECT 0.048 23.040 25.792 23.136 ;
      RECT 0.048 23.808 25.792 23.904 ;
      RECT 0.048 24.576 25.792 24.672 ;
      RECT 0.048 25.344 25.792 25.440 ;
      RECT 0.048 26.112 25.792 26.208 ;
      RECT 0.048 26.880 25.792 26.976 ;
      RECT 0.048 27.648 25.792 27.744 ;
      RECT 0.048 28.416 25.792 28.512 ;
      RECT 0.048 29.184 25.792 29.280 ;
      RECT 0.048 29.952 25.792 30.048 ;
      RECT 0.048 30.720 25.792 30.816 ;
      RECT 0.048 31.488 25.792 31.584 ;
      RECT 0.048 32.256 25.792 32.352 ;
      RECT 0.048 33.024 25.792 33.120 ;
      RECT 0.048 33.792 25.792 33.888 ;
      RECT 0.048 34.560 25.792 34.656 ;
      RECT 0.048 35.328 25.792 35.424 ;
      RECT 0.048 36.096 25.792 36.192 ;
      RECT 0.048 36.864 25.792 36.960 ;
      RECT 0.048 37.632 25.792 37.728 ;
      RECT 0.048 38.400 25.792 38.496 ;
      RECT 0.048 39.168 25.792 39.264 ;
      RECT 0.048 39.936 25.792 40.032 ;
      RECT 0.048 40.704 25.792 40.800 ;
      RECT 0.048 41.472 25.792 41.568 ;
      RECT 0.048 42.240 25.792 42.336 ;
      RECT 0.048 43.008 25.792 43.104 ;
      RECT 0.048 43.776 25.792 43.872 ;
      RECT 0.048 44.544 25.792 44.640 ;
      RECT 0.048 45.312 25.792 45.408 ;
      RECT 0.048 46.080 25.792 46.176 ;
    END
  END VSS
  PIN VDD
    DIRECTION INOUT ;
    USE POWER ;
    PORT
      LAYER M4 ;
      RECT 0.048 0.384 25.792 0.480 ;
      RECT 0.048 1.152 25.792 1.248 ;
      RECT 0.048 1.920 25.792 2.016 ;
      RECT 0.048 2.688 25.792 2.784 ;
      RECT 0.048 3.456 25.792 3.552 ;
      RECT 0.048 4.224 25.792 4.320 ;
      RECT 0.048 4.992 25.792 5.088 ;
      RECT 0.048 5.760 25.792 5.856 ;
      RECT 0.048 6.528 25.792 6.624 ;
      RECT 0.048 7.296 25.792 7.392 ;
      RECT 0.048 8.064 25.792 8.160 ;
      RECT 0.048 8.832 25.792 8.928 ;
      RECT 0.048 9.600 25.792 9.696 ;
      RECT 0.048 10.368 25.792 10.464 ;
      RECT 0.048 11.136 25.792 11.232 ;
      RECT 0.048 11.904 25.792 12.000 ;
      RECT 0.048 12.672 25.792 12.768 ;
      RECT 0.048 13.440 25.792 13.536 ;
      RECT 0.048 14.208 25.792 14.304 ;
      RECT 0.048 14.976 25.792 15.072 ;
      RECT 0.048 15.744 25.792 15.840 ;
      RECT 0.048 16.512 25.792 16.608 ;
      RECT 0.048 17.280 25.792 17.376 ;
      RECT 0.048 18.048 25.792 18.144 ;
      RECT 0.048 18.816 25.792 18.912 ;
      RECT 0.048 19.584 25.792 19.680 ;
      RECT 0.048 20.352 25.792 20.448 ;
      RECT 0.048 21.120 25.792 21.216 ;
      RECT 0.048 21.888 25.792 21.984 ;
      RECT 0.048 22.656 25.792 22.752 ;
      RECT 0.048 23.424 25.792 23.520 ;
      RECT 0.048 24.192 25.792 24.288 ;
      RECT 0.048 24.960 25.792 25.056 ;
      RECT 0.048 25.728 25.792 25.824 ;
      RECT 0.048 26.496 25.792 26.592 ;
      RECT 0.048 27.264 25.792 27.360 ;
      RECT 0.048 28.032 25.792 28.128 ;
      RECT 0.048 28.800 25.792 28.896 ;
      RECT 0.048 29.568 25.792 29.664 ;
      RECT 0.048 30.336 25.792 30.432 ;
      RECT 0.048 31.104 25.792 31.200 ;
      RECT 0.048 31.872 25.792 31.968 ;
      RECT 0.048 32.640 25.792 32.736 ;
      RECT 0.048 33.408 25.792 33.504 ;
      RECT 0.048 34.176 25.792 34.272 ;
      RECT 0.048 34.944 25.792 35.040 ;
      RECT 0.048 35.712 25.792 35.808 ;
      RECT 0.048 36.480 25.792 36.576 ;
      RECT 0.048 37.248 25.792 37.344 ;
      RECT 0.048 38.016 25.792 38.112 ;
      RECT 0.048 38.784 25.792 38.880 ;
      RECT 0.048 39.552 25.792 39.648 ;
      RECT 0.048 40.320 25.792 40.416 ;
      RECT 0.048 41.088 25.792 41.184 ;
      RECT 0.048 41.856 25.792 41.952 ;
      RECT 0.048 42.624 25.792 42.720 ;
      RECT 0.048 43.392 25.792 43.488 ;
      RECT 0.048 44.160 25.792 44.256 ;
      RECT 0.048 44.928 25.792 45.024 ;
      RECT 0.048 45.696 25.792 45.792 ;
    END
  END VDD
  OBS
    LAYER M1 ;
    RECT 0 0 25.840 46.200 ;
    LAYER M2 ;
    RECT 0 0 25.840 46.200 ;
    LAYER M3 ;
    RECT 0 0 25.840 46.200 ;
    LAYER M4 ;
    RECT 0 0 25.840 46.200 ;
  END
END fakeram7_tdp_512x32

END LIBRARY
